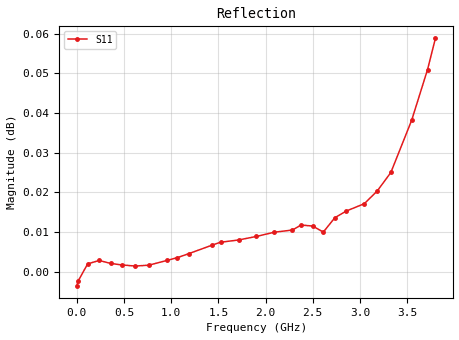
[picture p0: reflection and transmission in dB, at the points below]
! ListType=Lin
!!SAA-2 female open 0.1 to 3800MHz 500 points
# MHz S RI R 50
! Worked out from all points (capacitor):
!   500 points, 100 kHz to 3.8 GHz, reference 50 ohm
!   read as one part to ground: C = 973 fF near 15.33 MHz
!   lowest |Z| = 22.2 ohm at 3.8 GHz (marker M1)
!   S11 on the Smith chart (normalised r, x): 100 kHz: open; 761.6 MHz: -0.00, -4.24; 1.523 GHz: -0.00, -2.00; 2.285 GHz: -0.00, -1.20; 3.046 GHz: -0.00, -0.75; 3.8 GHz: -0.00, -0.44
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0.1  0.9996 -6.11e-05
15.33006  0.9997 -0.00937
114.3255  0.9978 -0.0697
236.1659  0.99 -0.1434
358.0064  0.9766 -0.2162
479.8469  0.9579 -0.2878
616.9174  0.9306 -0.3665
761.603  0.8948 -0.4469
951.9788  0.8372 -0.5475
1066.204  0.7972 -0.6044
1188.045  0.7503 -0.6619
1431.726  0.6444 -0.7657
1523.106  0.6009 -0.8004
1713.482  0.5043 -0.8646
1903.858  0.401 -0.9172
2094.233  0.2924 -0.9575
2284.609  0.18 -0.9849
2375.989  0.1252 -0.9935
2497.83  0.0516 -1
2612.055  -0.0176 -1.001
2733.896  -0.0913 -0.9974
2855.736  -0.1643 -0.9882
3046.112  -0.2764 -0.9631
3183.183  -0.3552 -0.9373
3327.868  -0.4359 -0.9032
3548.704  -0.5534 -0.8382
3716.235  -0.6366 -0.7788
3800  -0.6761 -0.746
